One B-rep face of a CAD part: STEP entity #143.
In plain terms, the planar face has unit normal (0, 0, -1).
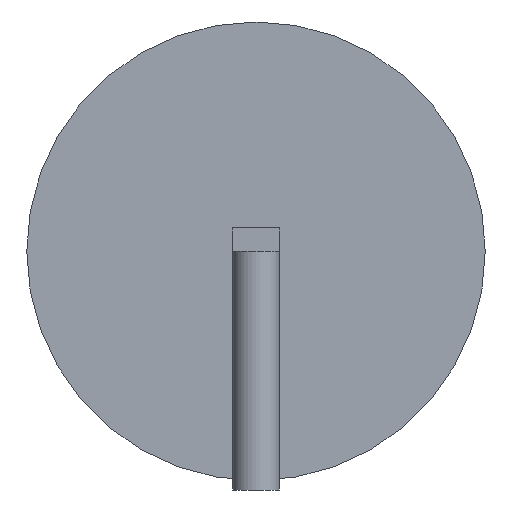
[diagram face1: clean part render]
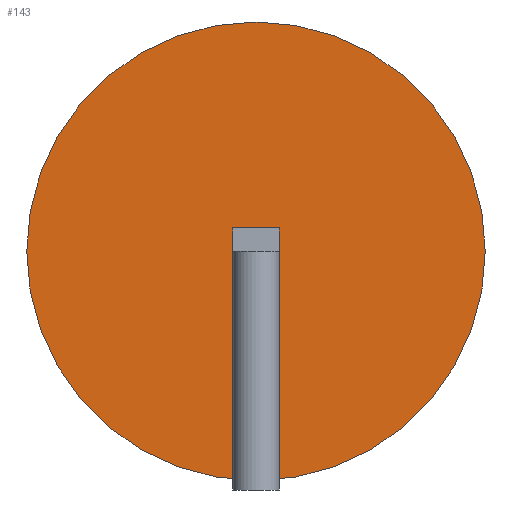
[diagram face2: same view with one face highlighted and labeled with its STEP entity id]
Its self-contained STEP definition (entity closure, numbers rounded to 3 decimals):
#65 = CYLINDRICAL_SURFACE('',#66,3.937);
#66 = AXIS2_PLACEMENT_3D('',#67,#68,#69);
#67 = CARTESIAN_POINT('',(0.,0.,0.));
#68 = DIRECTION('',(0.,0.,1.));
#69 = DIRECTION('',(1.,0.,-0.));
#90 = VERTEX_POINT('',#91);
#91 = CARTESIAN_POINT('',(3.937,0.,0.));
#112 = EDGE_CURVE('',#90,#90,#113,.T.);
#113 = SURFACE_CURVE('',#114,(#119,#126),.PCURVE_S1.);
#114 = CIRCLE('',#115,3.937);
#115 = AXIS2_PLACEMENT_3D('',#116,#117,#118);
#116 = CARTESIAN_POINT('',(0.,0.,0.));
#117 = DIRECTION('',(0.,0.,1.));
#118 = DIRECTION('',(1.,0.,-0.));
#119 = PCURVE('',#65,#120);
#120 = DEFINITIONAL_REPRESENTATION('',(#121),#125);
#121 = LINE('',#122,#123);
#122 = CARTESIAN_POINT('',(0.,0.));
#123 = VECTOR('',#124,1.);
#124 = DIRECTION('',(1.,0.));
#125 = ( GEOMETRIC_REPRESENTATION_CONTEXT(2) 
PARAMETRIC_REPRESENTATION_CONTEXT() REPRESENTATION_CONTEXT('2D SPACE',''
  ) );
#126 = PCURVE('',#127,#132);
#127 = PLANE('',#128);
#128 = AXIS2_PLACEMENT_3D('',#129,#130,#131);
#129 = CARTESIAN_POINT('',(0.,0.,0.));
#130 = DIRECTION('',(0.,0.,1.));
#131 = DIRECTION('',(1.,0.,-0.));
#132 = DEFINITIONAL_REPRESENTATION('',(#133),#137);
#133 = CIRCLE('',#134,3.937);
#134 = AXIS2_PLACEMENT_2D('',#135,#136);
#135 = CARTESIAN_POINT('',(0.,0.));
#136 = DIRECTION('',(1.,0.));
#137 = ( GEOMETRIC_REPRESENTATION_CONTEXT(2) 
PARAMETRIC_REPRESENTATION_CONTEXT() REPRESENTATION_CONTEXT('2D SPACE',''
  ) );
#143 = ADVANCED_FACE('',(#144),#127,.F.);
#144 = FACE_BOUND('',#145,.T.);
#145 = EDGE_LOOP('',(#146));
#146 = ORIENTED_EDGE('',*,*,#112,.F.);
